VERSION 5.7 ;
  NOWIREEXTENSIONATPIN ON ;
  DIVIDERCHAR "/" ;
  BUSBITCHARS "[]" ;
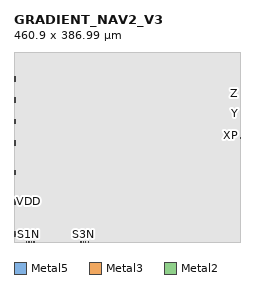
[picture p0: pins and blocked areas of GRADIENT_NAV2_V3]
MACRO GRADIENT_NAV2_V3
  CLASS BLOCK ;
  FOREIGN GRADIENT_NAV2_V3 ;
  ORIGIN 0.000 0.000 ;
  SIZE 460.900 BY 386.990 ;
  PIN VDD
    DIRECTION INOUT ;
    USE POWER ;
    PORT
      LAYER Metal5 ;
        RECT 0.000 76.725 3.000 86.725 ;
    END
    PORT
      LAYER Metal5 ;
        RECT 0.000 196.685 3.000 206.685 ;
    END
    PORT
      LAYER Metal5 ;
        RECT 0.000 283.950 3.000 293.900 ;
    END
  END VDD
  PIN VSS
    DIRECTION INOUT ;
    USE GROUND ;
    PORT
      LAYER Metal5 ;
        RECT 0.000 11.315 3.000 21.315 ;
    END
    PORT
      LAYER Metal5 ;
        RECT 0.000 137.155 3.000 146.645 ;
    END
    PORT
      LAYER Metal5 ;
        RECT 0.000 240.715 3.000 250.505 ;
    END
    PORT
      LAYER Metal5 ;
        RECT 0.000 327.510 3.000 337.300 ;
    END
  END VSS
  PIN XP
    DIRECTION OUTPUT ;
    USE SIGNAL ;
    PORT
      LAYER Metal3 ;
        RECT 460.380 216.860 460.900 217.140 ;
    END
  END XP
  PIN X
    DIRECTION OUTPUT ;
    USE SIGNAL ;
    PORT
      LAYER Metal3 ;
        RECT 460.380 211.820 460.900 212.100 ;
    END
  END X
  PIN XN
    DIRECTION OUTPUT ;
    USE SIGNAL ;
    PORT
      LAYER Metal3 ;
        RECT 460.380 206.780 460.900 207.060 ;
    END
  END XN
  PIN YP
    DIRECTION OUTPUT ;
    USE SIGNAL ;
    PORT
      LAYER Metal3 ;
        RECT 460.380 257.180 460.900 257.460 ;
    END
  END YP
  PIN Y
    DIRECTION OUTPUT ;
    USE SIGNAL ;
    PORT
      LAYER Metal3 ;
        RECT 460.380 262.220 460.900 262.500 ;
    END
  END Y
  PIN YN
    DIRECTION OUTPUT ;
    USE SIGNAL ;
    PORT
      LAYER Metal3 ;
        RECT 460.380 267.260 460.900 267.540 ;
    END
  END YN
  PIN ZP
    DIRECTION OUTPUT ;
    USE SIGNAL ;
    PORT
      LAYER Metal3 ;
        RECT 460.380 307.580 460.900 307.860 ;
    END
  END ZP
  PIN Z
    DIRECTION OUTPUT ;
    USE SIGNAL ;
    PORT
      LAYER Metal3 ;
        RECT 460.380 302.540 460.900 302.820 ;
    END
  END Z
  PIN ZN
    DIRECTION OUTPUT ;
    USE SIGNAL ;
    PORT
      LAYER Metal3 ;
        RECT 460.380 297.500 460.900 297.780 ;
    END
  END ZN
  PIN S2P
    DIRECTION INPUT ;
    USE SIGNAL ;
    PORT
      LAYER Metal2 ;
        RECT 40.460 0.000 40.740 0.520 ;
    END
  END S2P
  PIN S2N
    DIRECTION INPUT ;
    USE SIGNAL ;
    PORT
      LAYER Metal2 ;
        RECT 35.420 0.000 35.700 0.520 ;
    END
  END S2N
  PIN S4P
    DIRECTION INPUT ;
    USE SIGNAL ;
    PORT
      LAYER Metal2 ;
        RECT 151.340 0.000 151.620 0.520 ;
    END
  END S4P
  PIN S4N
    DIRECTION INPUT ;
    USE SIGNAL ;
    PORT
      LAYER Metal2 ;
        RECT 146.300 0.000 146.580 0.520 ;
    END
  END S4N
  PIN S3P
    DIRECTION INPUT ;
    USE SIGNAL ;
    PORT
      LAYER Metal2 ;
        RECT 136.220 0.000 136.500 0.520 ;
    END
  END S3P
  PIN S3N
    DIRECTION INPUT ;
    USE SIGNAL ;
    PORT
      LAYER Metal2 ;
        RECT 141.260 0.000 141.540 0.520 ;
    END
  END S3N
  PIN S1P
    DIRECTION INPUT ;
    USE SIGNAL ;
    PORT
      LAYER Metal2 ;
        RECT 25.340 0.000 25.620 0.520 ;
    END
  END S1P
  PIN S1N
    DIRECTION INPUT ;
    USE SIGNAL ;
    PORT
      LAYER Metal2 ;
        RECT 30.380 0.000 30.660 0.520 ;
    END
  END S1N
  OBS
      LAYER Metal1 ;
        RECT 0.000 0.000 460.900 386.990 ;
      LAYER Metal2 ;
        RECT 0.000 0.000 460.900 386.990 ;
      LAYER Metal3 ;
        RECT 0.000 0.000 460.900 386.990 ;
      LAYER Metal4 ;
        RECT 0.000 0.000 460.900 386.990 ;
      LAYER Metal5 ;
        RECT 0.000 0.000 460.900 386.990 ;
  END
END GRADIENT_NAV2_V3
